# Generated by FakeRAM 2.0
VERSION 5.7 ;
BUSBITCHARS "[]" ;
PROPERTYDEFINITIONS
  MACRO width INTEGER ;
  MACRO depth INTEGER ;
  MACRO banks INTEGER ;
END PROPERTYDEFINITIONS
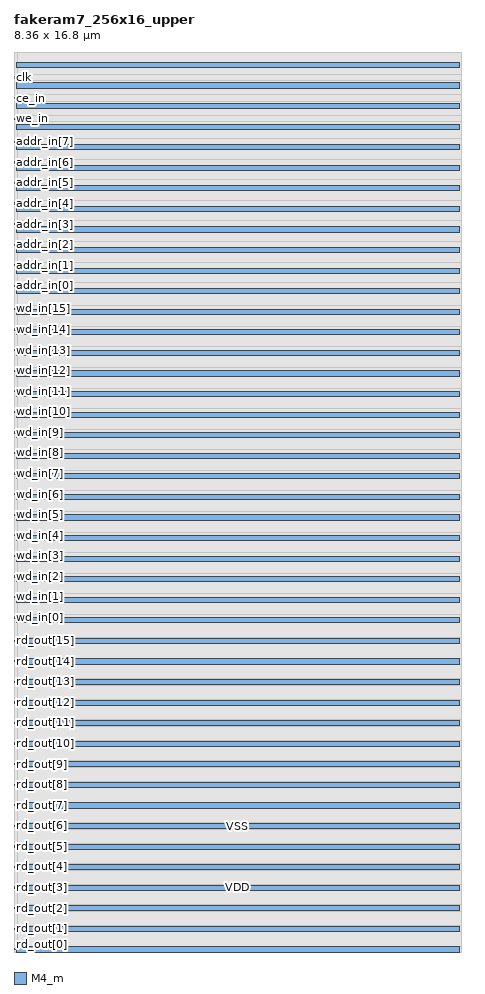
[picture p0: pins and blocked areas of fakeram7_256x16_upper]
MACRO fakeram7_256x16_upper
  PROPERTY width 16 ;
  PROPERTY depth 256 ;
  PROPERTY banks 2 ;
  FOREIGN fakeram7_256x16_upper 0 0 ;
  SYMMETRY X R90 ;
  SIZE 8.360 BY 16.800 ;
  CLASS BLOCK ;
  PIN rd_out[0]
    DIRECTION OUTPUT ;
    USE SIGNAL ;
    SHAPE ABUTMENT ;
    PORT
      LAYER M4_m ;
      RECT 0.000 0.039 0.024 0.063 ;
    END
  END rd_out[0]
  PIN rd_out[1]
    DIRECTION OUTPUT ;
    USE SIGNAL ;
    SHAPE ABUTMENT ;
    PORT
      LAYER M4_m ;
      RECT 0.000 0.423 0.024 0.447 ;
    END
  END rd_out[1]
  PIN rd_out[2]
    DIRECTION OUTPUT ;
    USE SIGNAL ;
    SHAPE ABUTMENT ;
    PORT
      LAYER M4_m ;
      RECT 0.000 0.807 0.024 0.831 ;
    END
  END rd_out[2]
  PIN rd_out[3]
    DIRECTION OUTPUT ;
    USE SIGNAL ;
    SHAPE ABUTMENT ;
    PORT
      LAYER M4_m ;
      RECT 0.000 1.191 0.024 1.215 ;
    END
  END rd_out[3]
  PIN rd_out[4]
    DIRECTION OUTPUT ;
    USE SIGNAL ;
    SHAPE ABUTMENT ;
    PORT
      LAYER M4_m ;
      RECT 0.000 1.575 0.024 1.599 ;
    END
  END rd_out[4]
  PIN rd_out[5]
    DIRECTION OUTPUT ;
    USE SIGNAL ;
    SHAPE ABUTMENT ;
    PORT
      LAYER M4_m ;
      RECT 0.000 1.959 0.024 1.983 ;
    END
  END rd_out[5]
  PIN rd_out[6]
    DIRECTION OUTPUT ;
    USE SIGNAL ;
    SHAPE ABUTMENT ;
    PORT
      LAYER M4_m ;
      RECT 0.000 2.343 0.024 2.367 ;
    END
  END rd_out[6]
  PIN rd_out[7]
    DIRECTION OUTPUT ;
    USE SIGNAL ;
    SHAPE ABUTMENT ;
    PORT
      LAYER M4_m ;
      RECT 0.000 2.727 0.024 2.751 ;
    END
  END rd_out[7]
  PIN rd_out[8]
    DIRECTION OUTPUT ;
    USE SIGNAL ;
    SHAPE ABUTMENT ;
    PORT
      LAYER M4_m ;
      RECT 0.000 3.111 0.024 3.135 ;
    END
  END rd_out[8]
  PIN rd_out[9]
    DIRECTION OUTPUT ;
    USE SIGNAL ;
    SHAPE ABUTMENT ;
    PORT
      LAYER M4_m ;
      RECT 0.000 3.495 0.024 3.519 ;
    END
  END rd_out[9]
  PIN rd_out[10]
    DIRECTION OUTPUT ;
    USE SIGNAL ;
    SHAPE ABUTMENT ;
    PORT
      LAYER M4_m ;
      RECT 0.000 3.879 0.024 3.903 ;
    END
  END rd_out[10]
  PIN rd_out[11]
    DIRECTION OUTPUT ;
    USE SIGNAL ;
    SHAPE ABUTMENT ;
    PORT
      LAYER M4_m ;
      RECT 0.000 4.263 0.024 4.287 ;
    END
  END rd_out[11]
  PIN rd_out[12]
    DIRECTION OUTPUT ;
    USE SIGNAL ;
    SHAPE ABUTMENT ;
    PORT
      LAYER M4_m ;
      RECT 0.000 4.647 0.024 4.671 ;
    END
  END rd_out[12]
  PIN rd_out[13]
    DIRECTION OUTPUT ;
    USE SIGNAL ;
    SHAPE ABUTMENT ;
    PORT
      LAYER M4_m ;
      RECT 0.000 5.031 0.024 5.055 ;
    END
  END rd_out[13]
  PIN rd_out[14]
    DIRECTION OUTPUT ;
    USE SIGNAL ;
    SHAPE ABUTMENT ;
    PORT
      LAYER M4_m ;
      RECT 0.000 5.415 0.024 5.439 ;
    END
  END rd_out[14]
  PIN rd_out[15]
    DIRECTION OUTPUT ;
    USE SIGNAL ;
    SHAPE ABUTMENT ;
    PORT
      LAYER M4_m ;
      RECT 0.000 5.799 0.024 5.823 ;
    END
  END rd_out[15]
  PIN wd_in[0]
    DIRECTION INPUT ;
    USE SIGNAL ;
    SHAPE ABUTMENT ;
    PORT
      LAYER M4_m ;
      RECT 0.000 6.231 0.024 6.255 ;
    END
  END wd_in[0]
  PIN wd_in[1]
    DIRECTION INPUT ;
    USE SIGNAL ;
    SHAPE ABUTMENT ;
    PORT
      LAYER M4_m ;
      RECT 0.000 6.615 0.024 6.639 ;
    END
  END wd_in[1]
  PIN wd_in[2]
    DIRECTION INPUT ;
    USE SIGNAL ;
    SHAPE ABUTMENT ;
    PORT
      LAYER M4_m ;
      RECT 0.000 6.999 0.024 7.023 ;
    END
  END wd_in[2]
  PIN wd_in[3]
    DIRECTION INPUT ;
    USE SIGNAL ;
    SHAPE ABUTMENT ;
    PORT
      LAYER M4_m ;
      RECT 0.000 7.383 0.024 7.407 ;
    END
  END wd_in[3]
  PIN wd_in[4]
    DIRECTION INPUT ;
    USE SIGNAL ;
    SHAPE ABUTMENT ;
    PORT
      LAYER M4_m ;
      RECT 0.000 7.767 0.024 7.791 ;
    END
  END wd_in[4]
  PIN wd_in[5]
    DIRECTION INPUT ;
    USE SIGNAL ;
    SHAPE ABUTMENT ;
    PORT
      LAYER M4_m ;
      RECT 0.000 8.151 0.024 8.175 ;
    END
  END wd_in[5]
  PIN wd_in[6]
    DIRECTION INPUT ;
    USE SIGNAL ;
    SHAPE ABUTMENT ;
    PORT
      LAYER M4_m ;
      RECT 0.000 8.535 0.024 8.559 ;
    END
  END wd_in[6]
  PIN wd_in[7]
    DIRECTION INPUT ;
    USE SIGNAL ;
    SHAPE ABUTMENT ;
    PORT
      LAYER M4_m ;
      RECT 0.000 8.919 0.024 8.943 ;
    END
  END wd_in[7]
  PIN wd_in[8]
    DIRECTION INPUT ;
    USE SIGNAL ;
    SHAPE ABUTMENT ;
    PORT
      LAYER M4_m ;
      RECT 0.000 9.303 0.024 9.327 ;
    END
  END wd_in[8]
  PIN wd_in[9]
    DIRECTION INPUT ;
    USE SIGNAL ;
    SHAPE ABUTMENT ;
    PORT
      LAYER M4_m ;
      RECT 0.000 9.687 0.024 9.711 ;
    END
  END wd_in[9]
  PIN wd_in[10]
    DIRECTION INPUT ;
    USE SIGNAL ;
    SHAPE ABUTMENT ;
    PORT
      LAYER M4_m ;
      RECT 0.000 10.071 0.024 10.095 ;
    END
  END wd_in[10]
  PIN wd_in[11]
    DIRECTION INPUT ;
    USE SIGNAL ;
    SHAPE ABUTMENT ;
    PORT
      LAYER M4_m ;
      RECT 0.000 10.455 0.024 10.479 ;
    END
  END wd_in[11]
  PIN wd_in[12]
    DIRECTION INPUT ;
    USE SIGNAL ;
    SHAPE ABUTMENT ;
    PORT
      LAYER M4_m ;
      RECT 0.000 10.839 0.024 10.863 ;
    END
  END wd_in[12]
  PIN wd_in[13]
    DIRECTION INPUT ;
    USE SIGNAL ;
    SHAPE ABUTMENT ;
    PORT
      LAYER M4_m ;
      RECT 0.000 11.223 0.024 11.247 ;
    END
  END wd_in[13]
  PIN wd_in[14]
    DIRECTION INPUT ;
    USE SIGNAL ;
    SHAPE ABUTMENT ;
    PORT
      LAYER M4_m ;
      RECT 0.000 11.607 0.024 11.631 ;
    END
  END wd_in[14]
  PIN wd_in[15]
    DIRECTION INPUT ;
    USE SIGNAL ;
    SHAPE ABUTMENT ;
    PORT
      LAYER M4_m ;
      RECT 0.000 11.991 0.024 12.015 ;
    END
  END wd_in[15]
  PIN addr_in[0]
    DIRECTION INPUT ;
    USE SIGNAL ;
    SHAPE ABUTMENT ;
    PORT
      LAYER M4_m ;
      RECT 0.000 12.423 0.024 12.447 ;
    END
  END addr_in[0]
  PIN addr_in[1]
    DIRECTION INPUT ;
    USE SIGNAL ;
    SHAPE ABUTMENT ;
    PORT
      LAYER M4_m ;
      RECT 0.000 12.807 0.024 12.831 ;
    END
  END addr_in[1]
  PIN addr_in[2]
    DIRECTION INPUT ;
    USE SIGNAL ;
    SHAPE ABUTMENT ;
    PORT
      LAYER M4_m ;
      RECT 0.000 13.191 0.024 13.215 ;
    END
  END addr_in[2]
  PIN addr_in[3]
    DIRECTION INPUT ;
    USE SIGNAL ;
    SHAPE ABUTMENT ;
    PORT
      LAYER M4_m ;
      RECT 0.000 13.575 0.024 13.599 ;
    END
  END addr_in[3]
  PIN addr_in[4]
    DIRECTION INPUT ;
    USE SIGNAL ;
    SHAPE ABUTMENT ;
    PORT
      LAYER M4_m ;
      RECT 0.000 13.959 0.024 13.983 ;
    END
  END addr_in[4]
  PIN addr_in[5]
    DIRECTION INPUT ;
    USE SIGNAL ;
    SHAPE ABUTMENT ;
    PORT
      LAYER M4_m ;
      RECT 0.000 14.343 0.024 14.367 ;
    END
  END addr_in[5]
  PIN addr_in[6]
    DIRECTION INPUT ;
    USE SIGNAL ;
    SHAPE ABUTMENT ;
    PORT
      LAYER M4_m ;
      RECT 0.000 14.727 0.024 14.751 ;
    END
  END addr_in[6]
  PIN addr_in[7]
    DIRECTION INPUT ;
    USE SIGNAL ;
    SHAPE ABUTMENT ;
    PORT
      LAYER M4_m ;
      RECT 0.000 15.111 0.024 15.135 ;
    END
  END addr_in[7]
  PIN we_in
    DIRECTION INPUT ;
    USE SIGNAL ;
    SHAPE ABUTMENT ;
    PORT
      LAYER M4_m ;
      RECT 0.000 15.543 0.024 15.567 ;
    END
  END we_in
  PIN ce_in
    DIRECTION INPUT ;
    USE SIGNAL ;
    SHAPE ABUTMENT ;
    PORT
      LAYER M4_m ;
      RECT 0.000 15.927 0.024 15.951 ;
    END
  END ce_in
  PIN clk
    DIRECTION INPUT ;
    USE SIGNAL ;
    SHAPE ABUTMENT ;
    PORT
      LAYER M4_m ;
      RECT 0.000 16.311 0.024 16.335 ;
    END
  END clk
  PIN VSS
    DIRECTION INOUT ;
    USE GROUND ;
    PORT
      LAYER M4_m ;
      RECT 0.048 0.000 8.312 0.096 ;
      RECT 0.048 0.768 8.312 0.864 ;
      RECT 0.048 1.536 8.312 1.632 ;
      RECT 0.048 2.304 8.312 2.400 ;
      RECT 0.048 3.072 8.312 3.168 ;
      RECT 0.048 3.840 8.312 3.936 ;
      RECT 0.048 4.608 8.312 4.704 ;
      RECT 0.048 5.376 8.312 5.472 ;
      RECT 0.048 6.144 8.312 6.240 ;
      RECT 0.048 6.912 8.312 7.008 ;
      RECT 0.048 7.680 8.312 7.776 ;
      RECT 0.048 8.448 8.312 8.544 ;
      RECT 0.048 9.216 8.312 9.312 ;
      RECT 0.048 9.984 8.312 10.080 ;
      RECT 0.048 10.752 8.312 10.848 ;
      RECT 0.048 11.520 8.312 11.616 ;
      RECT 0.048 12.288 8.312 12.384 ;
      RECT 0.048 13.056 8.312 13.152 ;
      RECT 0.048 13.824 8.312 13.920 ;
      RECT 0.048 14.592 8.312 14.688 ;
      RECT 0.048 15.360 8.312 15.456 ;
      RECT 0.048 16.128 8.312 16.224 ;
    END
  END VSS
  PIN VDD
    DIRECTION INOUT ;
    USE POWER ;
    PORT
      LAYER M4_m ;
      RECT 0.048 0.384 8.312 0.480 ;
      RECT 0.048 1.152 8.312 1.248 ;
      RECT 0.048 1.920 8.312 2.016 ;
      RECT 0.048 2.688 8.312 2.784 ;
      RECT 0.048 3.456 8.312 3.552 ;
      RECT 0.048 4.224 8.312 4.320 ;
      RECT 0.048 4.992 8.312 5.088 ;
      RECT 0.048 5.760 8.312 5.856 ;
      RECT 0.048 6.528 8.312 6.624 ;
      RECT 0.048 7.296 8.312 7.392 ;
      RECT 0.048 8.064 8.312 8.160 ;
      RECT 0.048 8.832 8.312 8.928 ;
      RECT 0.048 9.600 8.312 9.696 ;
      RECT 0.048 10.368 8.312 10.464 ;
      RECT 0.048 11.136 8.312 11.232 ;
      RECT 0.048 11.904 8.312 12.000 ;
      RECT 0.048 12.672 8.312 12.768 ;
      RECT 0.048 13.440 8.312 13.536 ;
      RECT 0.048 14.208 8.312 14.304 ;
      RECT 0.048 14.976 8.312 15.072 ;
      RECT 0.048 15.744 8.312 15.840 ;
      RECT 0.048 16.512 8.312 16.608 ;
    END
  END VDD
  OBS
    LAYER M1_m ;
    RECT 0 0 8.360 16.800 ;
    LAYER M2_m ;
    RECT 0 0 8.360 16.800 ;
    LAYER M3_m ;
    RECT 0.059 0.000 8.360 16.800 ;
    LAYER M4_m ;
    RECT 0.059 0.111 8.360 0.375 ;
    RECT 0.059 0.495 8.360 0.759 ;
    RECT 0.059 0.879 8.360 1.143 ;
    RECT 0.059 1.263 8.360 1.527 ;
    RECT 0.059 1.647 8.360 1.911 ;
    RECT 0.059 2.031 8.360 2.295 ;
    RECT 0.059 2.415 8.360 2.679 ;
    RECT 0.059 2.799 8.360 3.063 ;
    RECT 0.059 3.183 8.360 3.447 ;
    RECT 0.059 3.567 8.360 3.831 ;
    RECT 0.059 3.951 8.360 4.215 ;
    RECT 0.059 4.335 8.360 4.599 ;
    RECT 0.059 4.719 8.360 4.983 ;
    RECT 0.059 5.103 8.360 5.367 ;
    RECT 0.059 5.487 8.360 5.751 ;
    RECT 0.059 5.871 8.360 6.183 ;
    RECT 0.059 6.303 8.360 6.567 ;
    RECT 0.059 6.687 8.360 6.951 ;
    RECT 0.059 7.071 8.360 7.335 ;
    RECT 0.059 7.455 8.360 7.719 ;
    RECT 0.059 7.839 8.360 8.103 ;
    RECT 0.059 8.223 8.360 8.487 ;
    RECT 0.059 8.607 8.360 8.871 ;
    RECT 0.059 8.991 8.360 9.255 ;
    RECT 0.059 9.375 8.360 9.639 ;
    RECT 0.059 9.759 8.360 10.023 ;
    RECT 0.059 10.143 8.360 10.407 ;
    RECT 0.059 10.527 8.360 10.791 ;
    RECT 0.059 10.911 8.360 11.175 ;
    RECT 0.059 11.295 8.360 11.559 ;
    RECT 0.059 11.679 8.360 11.943 ;
    RECT 0.059 12.063 8.360 12.375 ;
    RECT 0.059 12.495 8.360 12.759 ;
    RECT 0.059 12.879 8.360 13.143 ;
    RECT 0.059 13.263 8.360 13.527 ;
    RECT 0.059 13.647 8.360 13.911 ;
    RECT 0.059 14.031 8.360 14.295 ;
    RECT 0.059 14.415 8.360 14.679 ;
    RECT 0.059 14.799 8.360 15.063 ;
    RECT 0.059 15.183 8.360 15.495 ;
    RECT 0.059 15.615 8.360 15.879 ;
    RECT 0.059 15.999 8.360 16.263 ;
    RECT 0.059 16.383 8.360 16.800 ;
  END
END fakeram7_256x16_upper

END LIBRARY
